# Generated by FakeRAM 2.0
VERSION 5.7 ;
BUSBITCHARS "[]" ;
PROPERTYDEFINITIONS
  MACRO width INTEGER ;
  MACRO depth INTEGER ;
  MACRO banks INTEGER ;
END PROPERTYDEFINITIONS
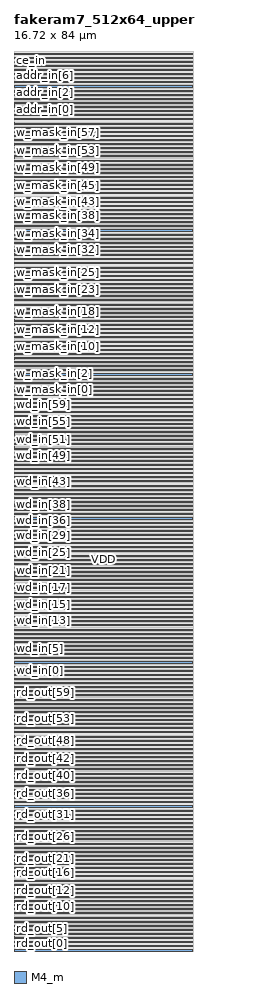
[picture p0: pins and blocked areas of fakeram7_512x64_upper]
MACRO fakeram7_512x64_upper
  PROPERTY width 64 ;
  PROPERTY depth 512 ;
  PROPERTY banks 2 ;
  FOREIGN fakeram7_512x64_upper 0 0 ;
  SYMMETRY X Y R90 ;
  SIZE 16.720 BY 84.000 ;
  CLASS COVER ;
  PIN rd_out[0]
    DIRECTION OUTPUT ;
    USE SIGNAL ;
    SHAPE ABUTMENT ;
    PORT
      LAYER M4_m ;
      RECT 0.000 0.039 0.024 0.063 ;
    END
  END rd_out[0]
  PIN rd_out[1]
    DIRECTION OUTPUT ;
    USE SIGNAL ;
    SHAPE ABUTMENT ;
    PORT
      LAYER M4_m ;
      RECT 0.000 0.471 0.024 0.495 ;
    END
  END rd_out[1]
  PIN rd_out[2]
    DIRECTION OUTPUT ;
    USE SIGNAL ;
    SHAPE ABUTMENT ;
    PORT
      LAYER M4_m ;
      RECT 0.000 0.855 0.024 0.879 ;
    END
  END rd_out[2]
  PIN rd_out[3]
    DIRECTION OUTPUT ;
    USE SIGNAL ;
    SHAPE ABUTMENT ;
    PORT
      LAYER M4_m ;
      RECT 0.000 1.287 0.024 1.311 ;
    END
  END rd_out[3]
  PIN rd_out[4]
    DIRECTION OUTPUT ;
    USE SIGNAL ;
    SHAPE ABUTMENT ;
    PORT
      LAYER M4_m ;
      RECT 0.000 1.671 0.024 1.695 ;
    END
  END rd_out[4]
  PIN rd_out[5]
    DIRECTION OUTPUT ;
    USE SIGNAL ;
    SHAPE ABUTMENT ;
    PORT
      LAYER M4_m ;
      RECT 0.000 2.103 0.024 2.127 ;
    END
  END rd_out[5]
  PIN rd_out[6]
    DIRECTION OUTPUT ;
    USE SIGNAL ;
    SHAPE ABUTMENT ;
    PORT
      LAYER M4_m ;
      RECT 0.000 2.487 0.024 2.511 ;
    END
  END rd_out[6]
  PIN rd_out[7]
    DIRECTION OUTPUT ;
    USE SIGNAL ;
    SHAPE ABUTMENT ;
    PORT
      LAYER M4_m ;
      RECT 0.000 2.919 0.024 2.943 ;
    END
  END rd_out[7]
  PIN rd_out[8]
    DIRECTION OUTPUT ;
    USE SIGNAL ;
    SHAPE ABUTMENT ;
    PORT
      LAYER M4_m ;
      RECT 0.000 3.303 0.024 3.327 ;
    END
  END rd_out[8]
  PIN rd_out[9]
    DIRECTION OUTPUT ;
    USE SIGNAL ;
    SHAPE ABUTMENT ;
    PORT
      LAYER M4_m ;
      RECT 0.000 3.735 0.024 3.759 ;
    END
  END rd_out[9]
  PIN rd_out[10]
    DIRECTION OUTPUT ;
    USE SIGNAL ;
    SHAPE ABUTMENT ;
    PORT
      LAYER M4_m ;
      RECT 0.000 4.119 0.024 4.143 ;
    END
  END rd_out[10]
  PIN rd_out[11]
    DIRECTION OUTPUT ;
    USE SIGNAL ;
    SHAPE ABUTMENT ;
    PORT
      LAYER M4_m ;
      RECT 0.000 4.551 0.024 4.575 ;
    END
  END rd_out[11]
  PIN rd_out[12]
    DIRECTION OUTPUT ;
    USE SIGNAL ;
    SHAPE ABUTMENT ;
    PORT
      LAYER M4_m ;
      RECT 0.000 4.935 0.024 4.959 ;
    END
  END rd_out[12]
  PIN rd_out[13]
    DIRECTION OUTPUT ;
    USE SIGNAL ;
    SHAPE ABUTMENT ;
    PORT
      LAYER M4_m ;
      RECT 0.000 5.367 0.024 5.391 ;
    END
  END rd_out[13]
  PIN rd_out[14]
    DIRECTION OUTPUT ;
    USE SIGNAL ;
    SHAPE ABUTMENT ;
    PORT
      LAYER M4_m ;
      RECT 0.000 5.751 0.024 5.775 ;
    END
  END rd_out[14]
  PIN rd_out[15]
    DIRECTION OUTPUT ;
    USE SIGNAL ;
    SHAPE ABUTMENT ;
    PORT
      LAYER M4_m ;
      RECT 0.000 6.183 0.024 6.207 ;
    END
  END rd_out[15]
  PIN rd_out[16]
    DIRECTION OUTPUT ;
    USE SIGNAL ;
    SHAPE ABUTMENT ;
    PORT
      LAYER M4_m ;
      RECT 0.000 6.567 0.024 6.591 ;
    END
  END rd_out[16]
  PIN rd_out[17]
    DIRECTION OUTPUT ;
    USE SIGNAL ;
    SHAPE ABUTMENT ;
    PORT
      LAYER M4_m ;
      RECT 0.000 6.999 0.024 7.023 ;
    END
  END rd_out[17]
  PIN rd_out[18]
    DIRECTION OUTPUT ;
    USE SIGNAL ;
    SHAPE ABUTMENT ;
    PORT
      LAYER M4_m ;
      RECT 0.000 7.383 0.024 7.407 ;
    END
  END rd_out[18]
  PIN rd_out[19]
    DIRECTION OUTPUT ;
    USE SIGNAL ;
    SHAPE ABUTMENT ;
    PORT
      LAYER M4_m ;
      RECT 0.000 7.815 0.024 7.839 ;
    END
  END rd_out[19]
  PIN rd_out[20]
    DIRECTION OUTPUT ;
    USE SIGNAL ;
    SHAPE ABUTMENT ;
    PORT
      LAYER M4_m ;
      RECT 0.000 8.199 0.024 8.223 ;
    END
  END rd_out[20]
  PIN rd_out[21]
    DIRECTION OUTPUT ;
    USE SIGNAL ;
    SHAPE ABUTMENT ;
    PORT
      LAYER M4_m ;
      RECT 0.000 8.631 0.024 8.655 ;
    END
  END rd_out[21]
  PIN rd_out[22]
    DIRECTION OUTPUT ;
    USE SIGNAL ;
    SHAPE ABUTMENT ;
    PORT
      LAYER M4_m ;
      RECT 0.000 9.015 0.024 9.039 ;
    END
  END rd_out[22]
  PIN rd_out[23]
    DIRECTION OUTPUT ;
    USE SIGNAL ;
    SHAPE ABUTMENT ;
    PORT
      LAYER M4_m ;
      RECT 0.000 9.447 0.024 9.471 ;
    END
  END rd_out[23]
  PIN rd_out[24]
    DIRECTION OUTPUT ;
    USE SIGNAL ;
    SHAPE ABUTMENT ;
    PORT
      LAYER M4_m ;
      RECT 0.000 9.831 0.024 9.855 ;
    END
  END rd_out[24]
  PIN rd_out[25]
    DIRECTION OUTPUT ;
    USE SIGNAL ;
    SHAPE ABUTMENT ;
    PORT
      LAYER M4_m ;
      RECT 0.000 10.263 0.024 10.287 ;
    END
  END rd_out[25]
  PIN rd_out[26]
    DIRECTION OUTPUT ;
    USE SIGNAL ;
    SHAPE ABUTMENT ;
    PORT
      LAYER M4_m ;
      RECT 0.000 10.647 0.024 10.671 ;
    END
  END rd_out[26]
  PIN rd_out[27]
    DIRECTION OUTPUT ;
    USE SIGNAL ;
    SHAPE ABUTMENT ;
    PORT
      LAYER M4_m ;
      RECT 0.000 11.079 0.024 11.103 ;
    END
  END rd_out[27]
  PIN rd_out[28]
    DIRECTION OUTPUT ;
    USE SIGNAL ;
    SHAPE ABUTMENT ;
    PORT
      LAYER M4_m ;
      RECT 0.000 11.463 0.024 11.487 ;
    END
  END rd_out[28]
  PIN rd_out[29]
    DIRECTION OUTPUT ;
    USE SIGNAL ;
    SHAPE ABUTMENT ;
    PORT
      LAYER M4_m ;
      RECT 0.000 11.895 0.024 11.919 ;
    END
  END rd_out[29]
  PIN rd_out[30]
    DIRECTION OUTPUT ;
    USE SIGNAL ;
    SHAPE ABUTMENT ;
    PORT
      LAYER M4_m ;
      RECT 0.000 12.279 0.024 12.303 ;
    END
  END rd_out[30]
  PIN rd_out[31]
    DIRECTION OUTPUT ;
    USE SIGNAL ;
    SHAPE ABUTMENT ;
    PORT
      LAYER M4_m ;
      RECT 0.000 12.711 0.024 12.735 ;
    END
  END rd_out[31]
  PIN rd_out[32]
    DIRECTION OUTPUT ;
    USE SIGNAL ;
    SHAPE ABUTMENT ;
    PORT
      LAYER M4_m ;
      RECT 0.000 13.095 0.024 13.119 ;
    END
  END rd_out[32]
  PIN rd_out[33]
    DIRECTION OUTPUT ;
    USE SIGNAL ;
    SHAPE ABUTMENT ;
    PORT
      LAYER M4_m ;
      RECT 0.000 13.527 0.024 13.551 ;
    END
  END rd_out[33]
  PIN rd_out[34]
    DIRECTION OUTPUT ;
    USE SIGNAL ;
    SHAPE ABUTMENT ;
    PORT
      LAYER M4_m ;
      RECT 0.000 13.911 0.024 13.935 ;
    END
  END rd_out[34]
  PIN rd_out[35]
    DIRECTION OUTPUT ;
    USE SIGNAL ;
    SHAPE ABUTMENT ;
    PORT
      LAYER M4_m ;
      RECT 0.000 14.343 0.024 14.367 ;
    END
  END rd_out[35]
  PIN rd_out[36]
    DIRECTION OUTPUT ;
    USE SIGNAL ;
    SHAPE ABUTMENT ;
    PORT
      LAYER M4_m ;
      RECT 0.000 14.727 0.024 14.751 ;
    END
  END rd_out[36]
  PIN rd_out[37]
    DIRECTION OUTPUT ;
    USE SIGNAL ;
    SHAPE ABUTMENT ;
    PORT
      LAYER M4_m ;
      RECT 0.000 15.159 0.024 15.183 ;
    END
  END rd_out[37]
  PIN rd_out[38]
    DIRECTION OUTPUT ;
    USE SIGNAL ;
    SHAPE ABUTMENT ;
    PORT
      LAYER M4_m ;
      RECT 0.000 15.543 0.024 15.567 ;
    END
  END rd_out[38]
  PIN rd_out[39]
    DIRECTION OUTPUT ;
    USE SIGNAL ;
    SHAPE ABUTMENT ;
    PORT
      LAYER M4_m ;
      RECT 0.000 15.975 0.024 15.999 ;
    END
  END rd_out[39]
  PIN rd_out[40]
    DIRECTION OUTPUT ;
    USE SIGNAL ;
    SHAPE ABUTMENT ;
    PORT
      LAYER M4_m ;
      RECT 0.000 16.359 0.024 16.383 ;
    END
  END rd_out[40]
  PIN rd_out[41]
    DIRECTION OUTPUT ;
    USE SIGNAL ;
    SHAPE ABUTMENT ;
    PORT
      LAYER M4_m ;
      RECT 0.000 16.791 0.024 16.815 ;
    END
  END rd_out[41]
  PIN rd_out[42]
    DIRECTION OUTPUT ;
    USE SIGNAL ;
    SHAPE ABUTMENT ;
    PORT
      LAYER M4_m ;
      RECT 0.000 17.175 0.024 17.199 ;
    END
  END rd_out[42]
  PIN rd_out[43]
    DIRECTION OUTPUT ;
    USE SIGNAL ;
    SHAPE ABUTMENT ;
    PORT
      LAYER M4_m ;
      RECT 0.000 17.607 0.024 17.631 ;
    END
  END rd_out[43]
  PIN rd_out[44]
    DIRECTION OUTPUT ;
    USE SIGNAL ;
    SHAPE ABUTMENT ;
    PORT
      LAYER M4_m ;
      RECT 0.000 17.991 0.024 18.015 ;
    END
  END rd_out[44]
  PIN rd_out[45]
    DIRECTION OUTPUT ;
    USE SIGNAL ;
    SHAPE ABUTMENT ;
    PORT
      LAYER M4_m ;
      RECT 0.000 18.423 0.024 18.447 ;
    END
  END rd_out[45]
  PIN rd_out[46]
    DIRECTION OUTPUT ;
    USE SIGNAL ;
    SHAPE ABUTMENT ;
    PORT
      LAYER M4_m ;
      RECT 0.000 18.807 0.024 18.831 ;
    END
  END rd_out[46]
  PIN rd_out[47]
    DIRECTION OUTPUT ;
    USE SIGNAL ;
    SHAPE ABUTMENT ;
    PORT
      LAYER M4_m ;
      RECT 0.000 19.239 0.024 19.263 ;
    END
  END rd_out[47]
  PIN rd_out[48]
    DIRECTION OUTPUT ;
    USE SIGNAL ;
    SHAPE ABUTMENT ;
    PORT
      LAYER M4_m ;
      RECT 0.000 19.623 0.024 19.647 ;
    END
  END rd_out[48]
  PIN rd_out[49]
    DIRECTION OUTPUT ;
    USE SIGNAL ;
    SHAPE ABUTMENT ;
    PORT
      LAYER M4_m ;
      RECT 0.000 20.055 0.024 20.079 ;
    END
  END rd_out[49]
  PIN rd_out[50]
    DIRECTION OUTPUT ;
    USE SIGNAL ;
    SHAPE ABUTMENT ;
    PORT
      LAYER M4_m ;
      RECT 0.000 20.439 0.024 20.463 ;
    END
  END rd_out[50]
  PIN rd_out[51]
    DIRECTION OUTPUT ;
    USE SIGNAL ;
    SHAPE ABUTMENT ;
    PORT
      LAYER M4_m ;
      RECT 0.000 20.871 0.024 20.895 ;
    END
  END rd_out[51]
  PIN rd_out[52]
    DIRECTION OUTPUT ;
    USE SIGNAL ;
    SHAPE ABUTMENT ;
    PORT
      LAYER M4_m ;
      RECT 0.000 21.255 0.024 21.279 ;
    END
  END rd_out[52]
  PIN rd_out[53]
    DIRECTION OUTPUT ;
    USE SIGNAL ;
    SHAPE ABUTMENT ;
    PORT
      LAYER M4_m ;
      RECT 0.000 21.687 0.024 21.711 ;
    END
  END rd_out[53]
  PIN rd_out[54]
    DIRECTION OUTPUT ;
    USE SIGNAL ;
    SHAPE ABUTMENT ;
    PORT
      LAYER M4_m ;
      RECT 0.000 22.071 0.024 22.095 ;
    END
  END rd_out[54]
  PIN rd_out[55]
    DIRECTION OUTPUT ;
    USE SIGNAL ;
    SHAPE ABUTMENT ;
    PORT
      LAYER M4_m ;
      RECT 0.000 22.503 0.024 22.527 ;
    END
  END rd_out[55]
  PIN rd_out[56]
    DIRECTION OUTPUT ;
    USE SIGNAL ;
    SHAPE ABUTMENT ;
    PORT
      LAYER M4_m ;
      RECT 0.000 22.887 0.024 22.911 ;
    END
  END rd_out[56]
  PIN rd_out[57]
    DIRECTION OUTPUT ;
    USE SIGNAL ;
    SHAPE ABUTMENT ;
    PORT
      LAYER M4_m ;
      RECT 0.000 23.319 0.024 23.343 ;
    END
  END rd_out[57]
  PIN rd_out[58]
    DIRECTION OUTPUT ;
    USE SIGNAL ;
    SHAPE ABUTMENT ;
    PORT
      LAYER M4_m ;
      RECT 0.000 23.703 0.024 23.727 ;
    END
  END rd_out[58]
  PIN rd_out[59]
    DIRECTION OUTPUT ;
    USE SIGNAL ;
    SHAPE ABUTMENT ;
    PORT
      LAYER M4_m ;
      RECT 0.000 24.135 0.024 24.159 ;
    END
  END rd_out[59]
  PIN rd_out[60]
    DIRECTION OUTPUT ;
    USE SIGNAL ;
    SHAPE ABUTMENT ;
    PORT
      LAYER M4_m ;
      RECT 0.000 24.519 0.024 24.543 ;
    END
  END rd_out[60]
  PIN rd_out[61]
    DIRECTION OUTPUT ;
    USE SIGNAL ;
    SHAPE ABUTMENT ;
    PORT
      LAYER M4_m ;
      RECT 0.000 24.951 0.024 24.975 ;
    END
  END rd_out[61]
  PIN rd_out[62]
    DIRECTION OUTPUT ;
    USE SIGNAL ;
    SHAPE ABUTMENT ;
    PORT
      LAYER M4_m ;
      RECT 0.000 25.335 0.024 25.359 ;
    END
  END rd_out[62]
  PIN rd_out[63]
    DIRECTION OUTPUT ;
    USE SIGNAL ;
    SHAPE ABUTMENT ;
    PORT
      LAYER M4_m ;
      RECT 0.000 25.767 0.024 25.791 ;
    END
  END rd_out[63]
  PIN wd_in[0]
    DIRECTION INPUT ;
    USE SIGNAL ;
    SHAPE ABUTMENT ;
    PORT
      LAYER M4_m ;
      RECT 0.000 26.199 0.024 26.223 ;
    END
  END wd_in[0]
  PIN wd_in[1]
    DIRECTION INPUT ;
    USE SIGNAL ;
    SHAPE ABUTMENT ;
    PORT
      LAYER M4_m ;
      RECT 0.000 26.631 0.024 26.655 ;
    END
  END wd_in[1]
  PIN wd_in[2]
    DIRECTION INPUT ;
    USE SIGNAL ;
    SHAPE ABUTMENT ;
    PORT
      LAYER M4_m ;
      RECT 0.000 27.015 0.024 27.039 ;
    END
  END wd_in[2]
  PIN wd_in[3]
    DIRECTION INPUT ;
    USE SIGNAL ;
    SHAPE ABUTMENT ;
    PORT
      LAYER M4_m ;
      RECT 0.000 27.447 0.024 27.471 ;
    END
  END wd_in[3]
  PIN wd_in[4]
    DIRECTION INPUT ;
    USE SIGNAL ;
    SHAPE ABUTMENT ;
    PORT
      LAYER M4_m ;
      RECT 0.000 27.831 0.024 27.855 ;
    END
  END wd_in[4]
  PIN wd_in[5]
    DIRECTION INPUT ;
    USE SIGNAL ;
    SHAPE ABUTMENT ;
    PORT
      LAYER M4_m ;
      RECT 0.000 28.263 0.024 28.287 ;
    END
  END wd_in[5]
  PIN wd_in[6]
    DIRECTION INPUT ;
    USE SIGNAL ;
    SHAPE ABUTMENT ;
    PORT
      LAYER M4_m ;
      RECT 0.000 28.647 0.024 28.671 ;
    END
  END wd_in[6]
  PIN wd_in[7]
    DIRECTION INPUT ;
    USE SIGNAL ;
    SHAPE ABUTMENT ;
    PORT
      LAYER M4_m ;
      RECT 0.000 29.079 0.024 29.103 ;
    END
  END wd_in[7]
  PIN wd_in[8]
    DIRECTION INPUT ;
    USE SIGNAL ;
    SHAPE ABUTMENT ;
    PORT
      LAYER M4_m ;
      RECT 0.000 29.463 0.024 29.487 ;
    END
  END wd_in[8]
  PIN wd_in[9]
    DIRECTION INPUT ;
    USE SIGNAL ;
    SHAPE ABUTMENT ;
    PORT
      LAYER M4_m ;
      RECT 0.000 29.895 0.024 29.919 ;
    END
  END wd_in[9]
  PIN wd_in[10]
    DIRECTION INPUT ;
    USE SIGNAL ;
    SHAPE ABUTMENT ;
    PORT
      LAYER M4_m ;
      RECT 0.000 30.279 0.024 30.303 ;
    END
  END wd_in[10]
  PIN wd_in[11]
    DIRECTION INPUT ;
    USE SIGNAL ;
    SHAPE ABUTMENT ;
    PORT
      LAYER M4_m ;
      RECT 0.000 30.711 0.024 30.735 ;
    END
  END wd_in[11]
  PIN wd_in[12]
    DIRECTION INPUT ;
    USE SIGNAL ;
    SHAPE ABUTMENT ;
    PORT
      LAYER M4_m ;
      RECT 0.000 31.095 0.024 31.119 ;
    END
  END wd_in[12]
  PIN wd_in[13]
    DIRECTION INPUT ;
    USE SIGNAL ;
    SHAPE ABUTMENT ;
    PORT
      LAYER M4_m ;
      RECT 0.000 31.527 0.024 31.551 ;
    END
  END wd_in[13]
  PIN wd_in[14]
    DIRECTION INPUT ;
    USE SIGNAL ;
    SHAPE ABUTMENT ;
    PORT
      LAYER M4_m ;
      RECT 0.000 31.911 0.024 31.935 ;
    END
  END wd_in[14]
  PIN wd_in[15]
    DIRECTION INPUT ;
    USE SIGNAL ;
    SHAPE ABUTMENT ;
    PORT
      LAYER M4_m ;
      RECT 0.000 32.343 0.024 32.367 ;
    END
  END wd_in[15]
  PIN wd_in[16]
    DIRECTION INPUT ;
    USE SIGNAL ;
    SHAPE ABUTMENT ;
    PORT
      LAYER M4_m ;
      RECT 0.000 32.727 0.024 32.751 ;
    END
  END wd_in[16]
  PIN wd_in[17]
    DIRECTION INPUT ;
    USE SIGNAL ;
    SHAPE ABUTMENT ;
    PORT
      LAYER M4_m ;
      RECT 0.000 33.159 0.024 33.183 ;
    END
  END wd_in[17]
  PIN wd_in[18]
    DIRECTION INPUT ;
    USE SIGNAL ;
    SHAPE ABUTMENT ;
    PORT
      LAYER M4_m ;
      RECT 0.000 33.543 0.024 33.567 ;
    END
  END wd_in[18]
  PIN wd_in[19]
    DIRECTION INPUT ;
    USE SIGNAL ;
    SHAPE ABUTMENT ;
    PORT
      LAYER M4_m ;
      RECT 0.000 33.975 0.024 33.999 ;
    END
  END wd_in[19]
  PIN wd_in[20]
    DIRECTION INPUT ;
    USE SIGNAL ;
    SHAPE ABUTMENT ;
    PORT
      LAYER M4_m ;
      RECT 0.000 34.359 0.024 34.383 ;
    END
  END wd_in[20]
  PIN wd_in[21]
    DIRECTION INPUT ;
    USE SIGNAL ;
    SHAPE ABUTMENT ;
    PORT
      LAYER M4_m ;
      RECT 0.000 34.791 0.024 34.815 ;
    END
  END wd_in[21]
  PIN wd_in[22]
    DIRECTION INPUT ;
    USE SIGNAL ;
    SHAPE ABUTMENT ;
    PORT
      LAYER M4_m ;
      RECT 0.000 35.175 0.024 35.199 ;
    END
  END wd_in[22]
  PIN wd_in[23]
    DIRECTION INPUT ;
    USE SIGNAL ;
    SHAPE ABUTMENT ;
    PORT
      LAYER M4_m ;
      RECT 0.000 35.607 0.024 35.631 ;
    END
  END wd_in[23]
  PIN wd_in[24]
    DIRECTION INPUT ;
    USE SIGNAL ;
    SHAPE ABUTMENT ;
    PORT
      LAYER M4_m ;
      RECT 0.000 35.991 0.024 36.015 ;
    END
  END wd_in[24]
  PIN wd_in[25]
    DIRECTION INPUT ;
    USE SIGNAL ;
    SHAPE ABUTMENT ;
    PORT
      LAYER M4_m ;
      RECT 0.000 36.423 0.024 36.447 ;
    END
  END wd_in[25]
  PIN wd_in[26]
    DIRECTION INPUT ;
    USE SIGNAL ;
    SHAPE ABUTMENT ;
    PORT
      LAYER M4_m ;
      RECT 0.000 36.807 0.024 36.831 ;
    END
  END wd_in[26]
  PIN wd_in[27]
    DIRECTION INPUT ;
    USE SIGNAL ;
    SHAPE ABUTMENT ;
    PORT
      LAYER M4_m ;
      RECT 0.000 37.239 0.024 37.263 ;
    END
  END wd_in[27]
  PIN wd_in[28]
    DIRECTION INPUT ;
    USE SIGNAL ;
    SHAPE ABUTMENT ;
    PORT
      LAYER M4_m ;
      RECT 0.000 37.623 0.024 37.647 ;
    END
  END wd_in[28]
  PIN wd_in[29]
    DIRECTION INPUT ;
    USE SIGNAL ;
    SHAPE ABUTMENT ;
    PORT
      LAYER M4_m ;
      RECT 0.000 38.055 0.024 38.079 ;
    END
  END wd_in[29]
  PIN wd_in[30]
    DIRECTION INPUT ;
    USE SIGNAL ;
    SHAPE ABUTMENT ;
    PORT
      LAYER M4_m ;
      RECT 0.000 38.439 0.024 38.463 ;
    END
  END wd_in[30]
  PIN wd_in[31]
    DIRECTION INPUT ;
    USE SIGNAL ;
    SHAPE ABUTMENT ;
    PORT
      LAYER M4_m ;
      RECT 0.000 38.871 0.024 38.895 ;
    END
  END wd_in[31]
  PIN wd_in[32]
    DIRECTION INPUT ;
    USE SIGNAL ;
    SHAPE ABUTMENT ;
    PORT
      LAYER M4_m ;
      RECT 0.000 39.255 0.024 39.279 ;
    END
  END wd_in[32]
  PIN wd_in[33]
    DIRECTION INPUT ;
    USE SIGNAL ;
    SHAPE ABUTMENT ;
    PORT
      LAYER M4_m ;
      RECT 0.000 39.687 0.024 39.711 ;
    END
  END wd_in[33]
  PIN wd_in[34]
    DIRECTION INPUT ;
    USE SIGNAL ;
    SHAPE ABUTMENT ;
    PORT
      LAYER M4_m ;
      RECT 0.000 40.071 0.024 40.095 ;
    END
  END wd_in[34]
  PIN wd_in[35]
    DIRECTION INPUT ;
    USE SIGNAL ;
    SHAPE ABUTMENT ;
    PORT
      LAYER M4_m ;
      RECT 0.000 40.503 0.024 40.527 ;
    END
  END wd_in[35]
  PIN wd_in[36]
    DIRECTION INPUT ;
    USE SIGNAL ;
    SHAPE ABUTMENT ;
    PORT
      LAYER M4_m ;
      RECT 0.000 40.887 0.024 40.911 ;
    END
  END wd_in[36]
  PIN wd_in[37]
    DIRECTION INPUT ;
    USE SIGNAL ;
    SHAPE ABUTMENT ;
    PORT
      LAYER M4_m ;
      RECT 0.000 41.319 0.024 41.343 ;
    END
  END wd_in[37]
  PIN wd_in[38]
    DIRECTION INPUT ;
    USE SIGNAL ;
    SHAPE ABUTMENT ;
    PORT
      LAYER M4_m ;
      RECT 0.000 41.703 0.024 41.727 ;
    END
  END wd_in[38]
  PIN wd_in[39]
    DIRECTION INPUT ;
    USE SIGNAL ;
    SHAPE ABUTMENT ;
    PORT
      LAYER M4_m ;
      RECT 0.000 42.135 0.024 42.159 ;
    END
  END wd_in[39]
  PIN wd_in[40]
    DIRECTION INPUT ;
    USE SIGNAL ;
    SHAPE ABUTMENT ;
    PORT
      LAYER M4_m ;
      RECT 0.000 42.519 0.024 42.543 ;
    END
  END wd_in[40]
  PIN wd_in[41]
    DIRECTION INPUT ;
    USE SIGNAL ;
    SHAPE ABUTMENT ;
    PORT
      LAYER M4_m ;
      RECT 0.000 42.951 0.024 42.975 ;
    END
  END wd_in[41]
  PIN wd_in[42]
    DIRECTION INPUT ;
    USE SIGNAL ;
    SHAPE ABUTMENT ;
    PORT
      LAYER M4_m ;
      RECT 0.000 43.335 0.024 43.359 ;
    END
  END wd_in[42]
  PIN wd_in[43]
    DIRECTION INPUT ;
    USE SIGNAL ;
    SHAPE ABUTMENT ;
    PORT
      LAYER M4_m ;
      RECT 0.000 43.767 0.024 43.791 ;
    END
  END wd_in[43]
  PIN wd_in[44]
    DIRECTION INPUT ;
    USE SIGNAL ;
    SHAPE ABUTMENT ;
    PORT
      LAYER M4_m ;
      RECT 0.000 44.151 0.024 44.175 ;
    END
  END wd_in[44]
  PIN wd_in[45]
    DIRECTION INPUT ;
    USE SIGNAL ;
    SHAPE ABUTMENT ;
    PORT
      LAYER M4_m ;
      RECT 0.000 44.583 0.024 44.607 ;
    END
  END wd_in[45]
  PIN wd_in[46]
    DIRECTION INPUT ;
    USE SIGNAL ;
    SHAPE ABUTMENT ;
    PORT
      LAYER M4_m ;
      RECT 0.000 44.967 0.024 44.991 ;
    END
  END wd_in[46]
  PIN wd_in[47]
    DIRECTION INPUT ;
    USE SIGNAL ;
    SHAPE ABUTMENT ;
    PORT
      LAYER M4_m ;
      RECT 0.000 45.399 0.024 45.423 ;
    END
  END wd_in[47]
  PIN wd_in[48]
    DIRECTION INPUT ;
    USE SIGNAL ;
    SHAPE ABUTMENT ;
    PORT
      LAYER M4_m ;
      RECT 0.000 45.783 0.024 45.807 ;
    END
  END wd_in[48]
  PIN wd_in[49]
    DIRECTION INPUT ;
    USE SIGNAL ;
    SHAPE ABUTMENT ;
    PORT
      LAYER M4_m ;
      RECT 0.000 46.215 0.024 46.239 ;
    END
  END wd_in[49]
  PIN wd_in[50]
    DIRECTION INPUT ;
    USE SIGNAL ;
    SHAPE ABUTMENT ;
    PORT
      LAYER M4_m ;
      RECT 0.000 46.599 0.024 46.623 ;
    END
  END wd_in[50]
  PIN wd_in[51]
    DIRECTION INPUT ;
    USE SIGNAL ;
    SHAPE ABUTMENT ;
    PORT
      LAYER M4_m ;
      RECT 0.000 47.031 0.024 47.055 ;
    END
  END wd_in[51]
  PIN wd_in[52]
    DIRECTION INPUT ;
    USE SIGNAL ;
    SHAPE ABUTMENT ;
    PORT
      LAYER M4_m ;
      RECT 0.000 47.415 0.024 47.439 ;
    END
  END wd_in[52]
  PIN wd_in[53]
    DIRECTION INPUT ;
    USE SIGNAL ;
    SHAPE ABUTMENT ;
    PORT
      LAYER M4_m ;
      RECT 0.000 47.847 0.024 47.871 ;
    END
  END wd_in[53]
  PIN wd_in[54]
    DIRECTION INPUT ;
    USE SIGNAL ;
    SHAPE ABUTMENT ;
    PORT
      LAYER M4_m ;
      RECT 0.000 48.231 0.024 48.255 ;
    END
  END wd_in[54]
  PIN wd_in[55]
    DIRECTION INPUT ;
    USE SIGNAL ;
    SHAPE ABUTMENT ;
    PORT
      LAYER M4_m ;
      RECT 0.000 48.663 0.024 48.687 ;
    END
  END wd_in[55]
  PIN wd_in[56]
    DIRECTION INPUT ;
    USE SIGNAL ;
    SHAPE ABUTMENT ;
    PORT
      LAYER M4_m ;
      RECT 0.000 49.047 0.024 49.071 ;
    END
  END wd_in[56]
  PIN wd_in[57]
    DIRECTION INPUT ;
    USE SIGNAL ;
    SHAPE ABUTMENT ;
    PORT
      LAYER M4_m ;
      RECT 0.000 49.479 0.024 49.503 ;
    END
  END wd_in[57]
  PIN wd_in[58]
    DIRECTION INPUT ;
    USE SIGNAL ;
    SHAPE ABUTMENT ;
    PORT
      LAYER M4_m ;
      RECT 0.000 49.863 0.024 49.887 ;
    END
  END wd_in[58]
  PIN wd_in[59]
    DIRECTION INPUT ;
    USE SIGNAL ;
    SHAPE ABUTMENT ;
    PORT
      LAYER M4_m ;
      RECT 0.000 50.295 0.024 50.319 ;
    END
  END wd_in[59]
  PIN wd_in[60]
    DIRECTION INPUT ;
    USE SIGNAL ;
    SHAPE ABUTMENT ;
    PORT
      LAYER M4_m ;
      RECT 0.000 50.679 0.024 50.703 ;
    END
  END wd_in[60]
  PIN wd_in[61]
    DIRECTION INPUT ;
    USE SIGNAL ;
    SHAPE ABUTMENT ;
    PORT
      LAYER M4_m ;
      RECT 0.000 51.111 0.024 51.135 ;
    END
  END wd_in[61]
  PIN wd_in[62]
    DIRECTION INPUT ;
    USE SIGNAL ;
    SHAPE ABUTMENT ;
    PORT
      LAYER M4_m ;
      RECT 0.000 51.495 0.024 51.519 ;
    END
  END wd_in[62]
  PIN wd_in[63]
    DIRECTION INPUT ;
    USE SIGNAL ;
    SHAPE ABUTMENT ;
    PORT
      LAYER M4_m ;
      RECT 0.000 51.927 0.024 51.951 ;
    END
  END wd_in[63]
  PIN w_mask_in[0]
    DIRECTION INPUT ;
    USE SIGNAL ;
    SHAPE ABUTMENT ;
    PORT
      LAYER M4_m ;
      RECT 0.000 52.359 0.024 52.383 ;
    END
  END w_mask_in[0]
  PIN w_mask_in[1]
    DIRECTION INPUT ;
    USE SIGNAL ;
    SHAPE ABUTMENT ;
    PORT
      LAYER M4_m ;
      RECT 0.000 52.791 0.024 52.815 ;
    END
  END w_mask_in[1]
  PIN w_mask_in[2]
    DIRECTION INPUT ;
    USE SIGNAL ;
    SHAPE ABUTMENT ;
    PORT
      LAYER M4_m ;
      RECT 0.000 53.175 0.024 53.199 ;
    END
  END w_mask_in[2]
  PIN w_mask_in[3]
    DIRECTION INPUT ;
    USE SIGNAL ;
    SHAPE ABUTMENT ;
    PORT
      LAYER M4_m ;
      RECT 0.000 53.607 0.024 53.631 ;
    END
  END w_mask_in[3]
  PIN w_mask_in[4]
    DIRECTION INPUT ;
    USE SIGNAL ;
    SHAPE ABUTMENT ;
    PORT
      LAYER M4_m ;
      RECT 0.000 53.991 0.024 54.015 ;
    END
  END w_mask_in[4]
  PIN w_mask_in[5]
    DIRECTION INPUT ;
    USE SIGNAL ;
    SHAPE ABUTMENT ;
    PORT
      LAYER M4_m ;
      RECT 0.000 54.423 0.024 54.447 ;
    END
  END w_mask_in[5]
  PIN w_mask_in[6]
    DIRECTION INPUT ;
    USE SIGNAL ;
    SHAPE ABUTMENT ;
    PORT
      LAYER M4_m ;
      RECT 0.000 54.807 0.024 54.831 ;
    END
  END w_mask_in[6]
  PIN w_mask_in[7]
    DIRECTION INPUT ;
    USE SIGNAL ;
    SHAPE ABUTMENT ;
    PORT
      LAYER M4_m ;
      RECT 0.000 55.239 0.024 55.263 ;
    END
  END w_mask_in[7]
  PIN w_mask_in[8]
    DIRECTION INPUT ;
    USE SIGNAL ;
    SHAPE ABUTMENT ;
    PORT
      LAYER M4_m ;
      RECT 0.000 55.623 0.024 55.647 ;
    END
  END w_mask_in[8]
  PIN w_mask_in[9]
    DIRECTION INPUT ;
    USE SIGNAL ;
    SHAPE ABUTMENT ;
    PORT
      LAYER M4_m ;
      RECT 0.000 56.055 0.024 56.079 ;
    END
  END w_mask_in[9]
  PIN w_mask_in[10]
    DIRECTION INPUT ;
    USE SIGNAL ;
    SHAPE ABUTMENT ;
    PORT
      LAYER M4_m ;
      RECT 0.000 56.439 0.024 56.463 ;
    END
  END w_mask_in[10]
  PIN w_mask_in[11]
    DIRECTION INPUT ;
    USE SIGNAL ;
    SHAPE ABUTMENT ;
    PORT
      LAYER M4_m ;
      RECT 0.000 56.871 0.024 56.895 ;
    END
  END w_mask_in[11]
  PIN w_mask_in[12]
    DIRECTION INPUT ;
    USE SIGNAL ;
    SHAPE ABUTMENT ;
    PORT
      LAYER M4_m ;
      RECT 0.000 57.255 0.024 57.279 ;
    END
  END w_mask_in[12]
  PIN w_mask_in[13]
    DIRECTION INPUT ;
    USE SIGNAL ;
    SHAPE ABUTMENT ;
    PORT
      LAYER M4_m ;
      RECT 0.000 57.687 0.024 57.711 ;
    END
  END w_mask_in[13]
  PIN w_mask_in[14]
    DIRECTION INPUT ;
    USE SIGNAL ;
    SHAPE ABUTMENT ;
    PORT
      LAYER M4_m ;
      RECT 0.000 58.071 0.024 58.095 ;
    END
  END w_mask_in[14]
  PIN w_mask_in[15]
    DIRECTION INPUT ;
    USE SIGNAL ;
    SHAPE ABUTMENT ;
    PORT
      LAYER M4_m ;
      RECT 0.000 58.503 0.024 58.527 ;
    END
  END w_mask_in[15]
  PIN w_mask_in[16]
    DIRECTION INPUT ;
    USE SIGNAL ;
    SHAPE ABUTMENT ;
    PORT
      LAYER M4_m ;
      RECT 0.000 58.887 0.024 58.911 ;
    END
  END w_mask_in[16]
  PIN w_mask_in[17]
    DIRECTION INPUT ;
    USE SIGNAL ;
    SHAPE ABUTMENT ;
    PORT
      LAYER M4_m ;
      RECT 0.000 59.319 0.024 59.343 ;
    END
  END w_mask_in[17]
  PIN w_mask_in[18]
    DIRECTION INPUT ;
    USE SIGNAL ;
    SHAPE ABUTMENT ;
    PORT
      LAYER M4_m ;
      RECT 0.000 59.703 0.024 59.727 ;
    END
  END w_mask_in[18]
  PIN w_mask_in[19]
    DIRECTION INPUT ;
    USE SIGNAL ;
    SHAPE ABUTMENT ;
    PORT
      LAYER M4_m ;
      RECT 0.000 60.135 0.024 60.159 ;
    END
  END w_mask_in[19]
  PIN w_mask_in[20]
    DIRECTION INPUT ;
    USE SIGNAL ;
    SHAPE ABUTMENT ;
    PORT
      LAYER M4_m ;
      RECT 0.000 60.519 0.024 60.543 ;
    END
  END w_mask_in[20]
  PIN w_mask_in[21]
    DIRECTION INPUT ;
    USE SIGNAL ;
    SHAPE ABUTMENT ;
    PORT
      LAYER M4_m ;
      RECT 0.000 60.951 0.024 60.975 ;
    END
  END w_mask_in[21]
  PIN w_mask_in[22]
    DIRECTION INPUT ;
    USE SIGNAL ;
    SHAPE ABUTMENT ;
    PORT
      LAYER M4_m ;
      RECT 0.000 61.335 0.024 61.359 ;
    END
  END w_mask_in[22]
  PIN w_mask_in[23]
    DIRECTION INPUT ;
    USE SIGNAL ;
    SHAPE ABUTMENT ;
    PORT
      LAYER M4_m ;
      RECT 0.000 61.767 0.024 61.791 ;
    END
  END w_mask_in[23]
  PIN w_mask_in[24]
    DIRECTION INPUT ;
    USE SIGNAL ;
    SHAPE ABUTMENT ;
    PORT
      LAYER M4_m ;
      RECT 0.000 62.151 0.024 62.175 ;
    END
  END w_mask_in[24]
  PIN w_mask_in[25]
    DIRECTION INPUT ;
    USE SIGNAL ;
    SHAPE ABUTMENT ;
    PORT
      LAYER M4_m ;
      RECT 0.000 62.583 0.024 62.607 ;
    END
  END w_mask_in[25]
  PIN w_mask_in[26]
    DIRECTION INPUT ;
    USE SIGNAL ;
    SHAPE ABUTMENT ;
    PORT
      LAYER M4_m ;
      RECT 0.000 62.967 0.024 62.991 ;
    END
  END w_mask_in[26]
  PIN w_mask_in[27]
    DIRECTION INPUT ;
    USE SIGNAL ;
    SHAPE ABUTMENT ;
    PORT
      LAYER M4_m ;
      RECT 0.000 63.399 0.024 63.423 ;
    END
  END w_mask_in[27]
  PIN w_mask_in[28]
    DIRECTION INPUT ;
    USE SIGNAL ;
    SHAPE ABUTMENT ;
    PORT
      LAYER M4_m ;
      RECT 0.000 63.783 0.024 63.807 ;
    END
  END w_mask_in[28]
  PIN w_mask_in[29]
    DIRECTION INPUT ;
    USE SIGNAL ;
    SHAPE ABUTMENT ;
    PORT
      LAYER M4_m ;
      RECT 0.000 64.215 0.024 64.239 ;
    END
  END w_mask_in[29]
  PIN w_mask_in[30]
    DIRECTION INPUT ;
    USE SIGNAL ;
    SHAPE ABUTMENT ;
    PORT
      LAYER M4_m ;
      RECT 0.000 64.599 0.024 64.623 ;
    END
  END w_mask_in[30]
  PIN w_mask_in[31]
    DIRECTION INPUT ;
    USE SIGNAL ;
    SHAPE ABUTMENT ;
    PORT
      LAYER M4_m ;
      RECT 0.000 65.031 0.024 65.055 ;
    END
  END w_mask_in[31]
  PIN w_mask_in[32]
    DIRECTION INPUT ;
    USE SIGNAL ;
    SHAPE ABUTMENT ;
    PORT
      LAYER M4_m ;
      RECT 0.000 65.415 0.024 65.439 ;
    END
  END w_mask_in[32]
  PIN w_mask_in[33]
    DIRECTION INPUT ;
    USE SIGNAL ;
    SHAPE ABUTMENT ;
    PORT
      LAYER M4_m ;
      RECT 0.000 65.847 0.024 65.871 ;
    END
  END w_mask_in[33]
  PIN w_mask_in[34]
    DIRECTION INPUT ;
    USE SIGNAL ;
    SHAPE ABUTMENT ;
    PORT
      LAYER M4_m ;
      RECT 0.000 66.231 0.024 66.255 ;
    END
  END w_mask_in[34]
  PIN w_mask_in[35]
    DIRECTION INPUT ;
    USE SIGNAL ;
    SHAPE ABUTMENT ;
    PORT
      LAYER M4_m ;
      RECT 0.000 66.663 0.024 66.687 ;
    END
  END w_mask_in[35]
  PIN w_mask_in[36]
    DIRECTION INPUT ;
    USE SIGNAL ;
    SHAPE ABUTMENT ;
    PORT
      LAYER M4_m ;
      RECT 0.000 67.047 0.024 67.071 ;
    END
  END w_mask_in[36]
  PIN w_mask_in[37]
    DIRECTION INPUT ;
    USE SIGNAL ;
    SHAPE ABUTMENT ;
    PORT
      LAYER M4_m ;
      RECT 0.000 67.479 0.024 67.503 ;
    END
  END w_mask_in[37]
  PIN w_mask_in[38]
    DIRECTION INPUT ;
    USE SIGNAL ;
    SHAPE ABUTMENT ;
    PORT
      LAYER M4_m ;
      RECT 0.000 67.863 0.024 67.887 ;
    END
  END w_mask_in[38]
  PIN w_mask_in[39]
    DIRECTION INPUT ;
    USE SIGNAL ;
    SHAPE ABUTMENT ;
    PORT
      LAYER M4_m ;
      RECT 0.000 68.295 0.024 68.319 ;
    END
  END w_mask_in[39]
  PIN w_mask_in[40]
    DIRECTION INPUT ;
    USE SIGNAL ;
    SHAPE ABUTMENT ;
    PORT
      LAYER M4_m ;
      RECT 0.000 68.679 0.024 68.703 ;
    END
  END w_mask_in[40]
  PIN w_mask_in[41]
    DIRECTION INPUT ;
    USE SIGNAL ;
    SHAPE ABUTMENT ;
    PORT
      LAYER M4_m ;
      RECT 0.000 69.111 0.024 69.135 ;
    END
  END w_mask_in[41]
  PIN w_mask_in[42]
    DIRECTION INPUT ;
    USE SIGNAL ;
    SHAPE ABUTMENT ;
    PORT
      LAYER M4_m ;
      RECT 0.000 69.495 0.024 69.519 ;
    END
  END w_mask_in[42]
  PIN w_mask_in[43]
    DIRECTION INPUT ;
    USE SIGNAL ;
    SHAPE ABUTMENT ;
    PORT
      LAYER M4_m ;
      RECT 0.000 69.927 0.024 69.951 ;
    END
  END w_mask_in[43]
  PIN w_mask_in[44]
    DIRECTION INPUT ;
    USE SIGNAL ;
    SHAPE ABUTMENT ;
    PORT
      LAYER M4_m ;
      RECT 0.000 70.311 0.024 70.335 ;
    END
  END w_mask_in[44]
  PIN w_mask_in[45]
    DIRECTION INPUT ;
    USE SIGNAL ;
    SHAPE ABUTMENT ;
    PORT
      LAYER M4_m ;
      RECT 0.000 70.743 0.024 70.767 ;
    END
  END w_mask_in[45]
  PIN w_mask_in[46]
    DIRECTION INPUT ;
    USE SIGNAL ;
    SHAPE ABUTMENT ;
    PORT
      LAYER M4_m ;
      RECT 0.000 71.127 0.024 71.151 ;
    END
  END w_mask_in[46]
  PIN w_mask_in[47]
    DIRECTION INPUT ;
    USE SIGNAL ;
    SHAPE ABUTMENT ;
    PORT
      LAYER M4_m ;
      RECT 0.000 71.559 0.024 71.583 ;
    END
  END w_mask_in[47]
  PIN w_mask_in[48]
    DIRECTION INPUT ;
    USE SIGNAL ;
    SHAPE ABUTMENT ;
    PORT
      LAYER M4_m ;
      RECT 0.000 71.943 0.024 71.967 ;
    END
  END w_mask_in[48]
  PIN w_mask_in[49]
    DIRECTION INPUT ;
    USE SIGNAL ;
    SHAPE ABUTMENT ;
    PORT
      LAYER M4_m ;
      RECT 0.000 72.375 0.024 72.399 ;
    END
  END w_mask_in[49]
  PIN w_mask_in[50]
    DIRECTION INPUT ;
    USE SIGNAL ;
    SHAPE ABUTMENT ;
    PORT
      LAYER M4_m ;
      RECT 0.000 72.759 0.024 72.783 ;
    END
  END w_mask_in[50]
  PIN w_mask_in[51]
    DIRECTION INPUT ;
    USE SIGNAL ;
    SHAPE ABUTMENT ;
    PORT
      LAYER M4_m ;
      RECT 0.000 73.191 0.024 73.215 ;
    END
  END w_mask_in[51]
  PIN w_mask_in[52]
    DIRECTION INPUT ;
    USE SIGNAL ;
    SHAPE ABUTMENT ;
    PORT
      LAYER M4_m ;
      RECT 0.000 73.575 0.024 73.599 ;
    END
  END w_mask_in[52]
  PIN w_mask_in[53]
    DIRECTION INPUT ;
    USE SIGNAL ;
    SHAPE ABUTMENT ;
    PORT
      LAYER M4_m ;
      RECT 0.000 74.007 0.024 74.031 ;
    END
  END w_mask_in[53]
  PIN w_mask_in[54]
    DIRECTION INPUT ;
    USE SIGNAL ;
    SHAPE ABUTMENT ;
    PORT
      LAYER M4_m ;
      RECT 0.000 74.391 0.024 74.415 ;
    END
  END w_mask_in[54]
  PIN w_mask_in[55]
    DIRECTION INPUT ;
    USE SIGNAL ;
    SHAPE ABUTMENT ;
    PORT
      LAYER M4_m ;
      RECT 0.000 74.823 0.024 74.847 ;
    END
  END w_mask_in[55]
  PIN w_mask_in[56]
    DIRECTION INPUT ;
    USE SIGNAL ;
    SHAPE ABUTMENT ;
    PORT
      LAYER M4_m ;
      RECT 0.000 75.207 0.024 75.231 ;
    END
  END w_mask_in[56]
  PIN w_mask_in[57]
    DIRECTION INPUT ;
    USE SIGNAL ;
    SHAPE ABUTMENT ;
    PORT
      LAYER M4_m ;
      RECT 0.000 75.639 0.024 75.663 ;
    END
  END w_mask_in[57]
  PIN w_mask_in[58]
    DIRECTION INPUT ;
    USE SIGNAL ;
    SHAPE ABUTMENT ;
    PORT
      LAYER M4_m ;
      RECT 0.000 76.023 0.024 76.047 ;
    END
  END w_mask_in[58]
  PIN w_mask_in[59]
    DIRECTION INPUT ;
    USE SIGNAL ;
    SHAPE ABUTMENT ;
    PORT
      LAYER M4_m ;
      RECT 0.000 76.455 0.024 76.479 ;
    END
  END w_mask_in[59]
  PIN w_mask_in[60]
    DIRECTION INPUT ;
    USE SIGNAL ;
    SHAPE ABUTMENT ;
    PORT
      LAYER M4_m ;
      RECT 0.000 76.839 0.024 76.863 ;
    END
  END w_mask_in[60]
  PIN w_mask_in[61]
    DIRECTION INPUT ;
    USE SIGNAL ;
    SHAPE ABUTMENT ;
    PORT
      LAYER M4_m ;
      RECT 0.000 77.271 0.024 77.295 ;
    END
  END w_mask_in[61]
  PIN w_mask_in[62]
    DIRECTION INPUT ;
    USE SIGNAL ;
    SHAPE ABUTMENT ;
    PORT
      LAYER M4_m ;
      RECT 0.000 77.655 0.024 77.679 ;
    END
  END w_mask_in[62]
  PIN w_mask_in[63]
    DIRECTION INPUT ;
    USE SIGNAL ;
    SHAPE ABUTMENT ;
    PORT
      LAYER M4_m ;
      RECT 0.000 78.087 0.024 78.111 ;
    END
  END w_mask_in[63]
  PIN addr_in[0]
    DIRECTION INPUT ;
    USE SIGNAL ;
    SHAPE ABUTMENT ;
    PORT
      LAYER M4_m ;
      RECT 0.000 78.519 0.024 78.543 ;
    END
  END addr_in[0]
  PIN addr_in[1]
    DIRECTION INPUT ;
    USE SIGNAL ;
    SHAPE ABUTMENT ;
    PORT
      LAYER M4_m ;
      RECT 0.000 78.951 0.024 78.975 ;
    END
  END addr_in[1]
  PIN addr_in[2]
    DIRECTION INPUT ;
    USE SIGNAL ;
    SHAPE ABUTMENT ;
    PORT
      LAYER M4_m ;
      RECT 0.000 79.335 0.024 79.359 ;
    END
  END addr_in[2]
  PIN addr_in[3]
    DIRECTION INPUT ;
    USE SIGNAL ;
    SHAPE ABUTMENT ;
    PORT
      LAYER M4_m ;
      RECT 0.000 79.767 0.024 79.791 ;
    END
  END addr_in[3]
  PIN addr_in[4]
    DIRECTION INPUT ;
    USE SIGNAL ;
    SHAPE ABUTMENT ;
    PORT
      LAYER M4_m ;
      RECT 0.000 80.151 0.024 80.175 ;
    END
  END addr_in[4]
  PIN addr_in[5]
    DIRECTION INPUT ;
    USE SIGNAL ;
    SHAPE ABUTMENT ;
    PORT
      LAYER M4_m ;
      RECT 0.000 80.583 0.024 80.607 ;
    END
  END addr_in[5]
  PIN addr_in[6]
    DIRECTION INPUT ;
    USE SIGNAL ;
    SHAPE ABUTMENT ;
    PORT
      LAYER M4_m ;
      RECT 0.000 80.967 0.024 80.991 ;
    END
  END addr_in[6]
  PIN addr_in[7]
    DIRECTION INPUT ;
    USE SIGNAL ;
    SHAPE ABUTMENT ;
    PORT
      LAYER M4_m ;
      RECT 0.000 81.399 0.024 81.423 ;
    END
  END addr_in[7]
  PIN addr_in[8]
    DIRECTION INPUT ;
    USE SIGNAL ;
    SHAPE ABUTMENT ;
    PORT
      LAYER M4_m ;
      RECT 0.000 81.783 0.024 81.807 ;
    END
  END addr_in[8]
  PIN we_in
    DIRECTION INPUT ;
    USE SIGNAL ;
    SHAPE ABUTMENT ;
    PORT
      LAYER M4_m ;
      RECT 0.000 82.263 0.024 82.287 ;
    END
  END we_in
  PIN ce_in
    DIRECTION INPUT ;
    USE SIGNAL ;
    SHAPE ABUTMENT ;
    PORT
      LAYER M4_m ;
      RECT 0.000 82.647 0.024 82.671 ;
    END
  END ce_in
  PIN clk
    DIRECTION INPUT ;
    USE SIGNAL ;
    SHAPE ABUTMENT ;
    PORT
      LAYER M4_m ;
      RECT 0.000 83.079 0.024 83.103 ;
    END
  END clk
  PIN VSS
    DIRECTION INOUT ;
    USE GROUND ;
    PORT
      LAYER M4_m ;
      RECT 0.048 0.000 16.672 0.096 ;
      RECT 0.048 0.768 16.672 0.864 ;
      RECT 0.048 1.536 16.672 1.632 ;
      RECT 0.048 2.304 16.672 2.400 ;
      RECT 0.048 3.072 16.672 3.168 ;
      RECT 0.048 3.840 16.672 3.936 ;
      RECT 0.048 4.608 16.672 4.704 ;
      RECT 0.048 5.376 16.672 5.472 ;
      RECT 0.048 6.144 16.672 6.240 ;
      RECT 0.048 6.912 16.672 7.008 ;
      RECT 0.048 7.680 16.672 7.776 ;
      RECT 0.048 8.448 16.672 8.544 ;
      RECT 0.048 9.216 16.672 9.312 ;
      RECT 0.048 9.984 16.672 10.080 ;
      RECT 0.048 10.752 16.672 10.848 ;
      RECT 0.048 11.520 16.672 11.616 ;
      RECT 0.048 12.288 16.672 12.384 ;
      RECT 0.048 13.056 16.672 13.152 ;
      RECT 0.048 13.824 16.672 13.920 ;
      RECT 0.048 14.592 16.672 14.688 ;
      RECT 0.048 15.360 16.672 15.456 ;
      RECT 0.048 16.128 16.672 16.224 ;
      RECT 0.048 16.896 16.672 16.992 ;
      RECT 0.048 17.664 16.672 17.760 ;
      RECT 0.048 18.432 16.672 18.528 ;
      RECT 0.048 19.200 16.672 19.296 ;
      RECT 0.048 19.968 16.672 20.064 ;
      RECT 0.048 20.736 16.672 20.832 ;
      RECT 0.048 21.504 16.672 21.600 ;
      RECT 0.048 22.272 16.672 22.368 ;
      RECT 0.048 23.040 16.672 23.136 ;
      RECT 0.048 23.808 16.672 23.904 ;
      RECT 0.048 24.576 16.672 24.672 ;
      RECT 0.048 25.344 16.672 25.440 ;
      RECT 0.048 26.112 16.672 26.208 ;
      RECT 0.048 26.880 16.672 26.976 ;
      RECT 0.048 27.648 16.672 27.744 ;
      RECT 0.048 28.416 16.672 28.512 ;
      RECT 0.048 29.184 16.672 29.280 ;
      RECT 0.048 29.952 16.672 30.048 ;
      RECT 0.048 30.720 16.672 30.816 ;
      RECT 0.048 31.488 16.672 31.584 ;
      RECT 0.048 32.256 16.672 32.352 ;
      RECT 0.048 33.024 16.672 33.120 ;
      RECT 0.048 33.792 16.672 33.888 ;
      RECT 0.048 34.560 16.672 34.656 ;
      RECT 0.048 35.328 16.672 35.424 ;
      RECT 0.048 36.096 16.672 36.192 ;
      RECT 0.048 36.864 16.672 36.960 ;
      RECT 0.048 37.632 16.672 37.728 ;
      RECT 0.048 38.400 16.672 38.496 ;
      RECT 0.048 39.168 16.672 39.264 ;
      RECT 0.048 39.936 16.672 40.032 ;
      RECT 0.048 40.704 16.672 40.800 ;
      RECT 0.048 41.472 16.672 41.568 ;
      RECT 0.048 42.240 16.672 42.336 ;
      RECT 0.048 43.008 16.672 43.104 ;
      RECT 0.048 43.776 16.672 43.872 ;
      RECT 0.048 44.544 16.672 44.640 ;
      RECT 0.048 45.312 16.672 45.408 ;
      RECT 0.048 46.080 16.672 46.176 ;
      RECT 0.048 46.848 16.672 46.944 ;
      RECT 0.048 47.616 16.672 47.712 ;
      RECT 0.048 48.384 16.672 48.480 ;
      RECT 0.048 49.152 16.672 49.248 ;
      RECT 0.048 49.920 16.672 50.016 ;
      RECT 0.048 50.688 16.672 50.784 ;
      RECT 0.048 51.456 16.672 51.552 ;
      RECT 0.048 52.224 16.672 52.320 ;
      RECT 0.048 52.992 16.672 53.088 ;
      RECT 0.048 53.760 16.672 53.856 ;
      RECT 0.048 54.528 16.672 54.624 ;
      RECT 0.048 55.296 16.672 55.392 ;
      RECT 0.048 56.064 16.672 56.160 ;
      RECT 0.048 56.832 16.672 56.928 ;
      RECT 0.048 57.600 16.672 57.696 ;
      RECT 0.048 58.368 16.672 58.464 ;
      RECT 0.048 59.136 16.672 59.232 ;
      RECT 0.048 59.904 16.672 60.000 ;
      RECT 0.048 60.672 16.672 60.768 ;
      RECT 0.048 61.440 16.672 61.536 ;
      RECT 0.048 62.208 16.672 62.304 ;
      RECT 0.048 62.976 16.672 63.072 ;
      RECT 0.048 63.744 16.672 63.840 ;
      RECT 0.048 64.512 16.672 64.608 ;
      RECT 0.048 65.280 16.672 65.376 ;
      RECT 0.048 66.048 16.672 66.144 ;
      RECT 0.048 66.816 16.672 66.912 ;
      RECT 0.048 67.584 16.672 67.680 ;
      RECT 0.048 68.352 16.672 68.448 ;
      RECT 0.048 69.120 16.672 69.216 ;
      RECT 0.048 69.888 16.672 69.984 ;
      RECT 0.048 70.656 16.672 70.752 ;
      RECT 0.048 71.424 16.672 71.520 ;
      RECT 0.048 72.192 16.672 72.288 ;
      RECT 0.048 72.960 16.672 73.056 ;
      RECT 0.048 73.728 16.672 73.824 ;
      RECT 0.048 74.496 16.672 74.592 ;
      RECT 0.048 75.264 16.672 75.360 ;
      RECT 0.048 76.032 16.672 76.128 ;
      RECT 0.048 76.800 16.672 76.896 ;
      RECT 0.048 77.568 16.672 77.664 ;
      RECT 0.048 78.336 16.672 78.432 ;
      RECT 0.048 79.104 16.672 79.200 ;
      RECT 0.048 79.872 16.672 79.968 ;
      RECT 0.048 80.640 16.672 80.736 ;
      RECT 0.048 81.408 16.672 81.504 ;
      RECT 0.048 82.176 16.672 82.272 ;
      RECT 0.048 82.944 16.672 83.040 ;
      RECT 0.048 83.712 16.672 83.808 ;
    END
  END VSS
  PIN VDD
    DIRECTION INOUT ;
    USE POWER ;
    PORT
      LAYER M4_m ;
      RECT 0.048 0.384 16.672 0.480 ;
      RECT 0.048 1.152 16.672 1.248 ;
      RECT 0.048 1.920 16.672 2.016 ;
      RECT 0.048 2.688 16.672 2.784 ;
      RECT 0.048 3.456 16.672 3.552 ;
      RECT 0.048 4.224 16.672 4.320 ;
      RECT 0.048 4.992 16.672 5.088 ;
      RECT 0.048 5.760 16.672 5.856 ;
      RECT 0.048 6.528 16.672 6.624 ;
      RECT 0.048 7.296 16.672 7.392 ;
      RECT 0.048 8.064 16.672 8.160 ;
      RECT 0.048 8.832 16.672 8.928 ;
      RECT 0.048 9.600 16.672 9.696 ;
      RECT 0.048 10.368 16.672 10.464 ;
      RECT 0.048 11.136 16.672 11.232 ;
      RECT 0.048 11.904 16.672 12.000 ;
      RECT 0.048 12.672 16.672 12.768 ;
      RECT 0.048 13.440 16.672 13.536 ;
      RECT 0.048 14.208 16.672 14.304 ;
      RECT 0.048 14.976 16.672 15.072 ;
      RECT 0.048 15.744 16.672 15.840 ;
      RECT 0.048 16.512 16.672 16.608 ;
      RECT 0.048 17.280 16.672 17.376 ;
      RECT 0.048 18.048 16.672 18.144 ;
      RECT 0.048 18.816 16.672 18.912 ;
      RECT 0.048 19.584 16.672 19.680 ;
      RECT 0.048 20.352 16.672 20.448 ;
      RECT 0.048 21.120 16.672 21.216 ;
      RECT 0.048 21.888 16.672 21.984 ;
      RECT 0.048 22.656 16.672 22.752 ;
      RECT 0.048 23.424 16.672 23.520 ;
      RECT 0.048 24.192 16.672 24.288 ;
      RECT 0.048 24.960 16.672 25.056 ;
      RECT 0.048 25.728 16.672 25.824 ;
      RECT 0.048 26.496 16.672 26.592 ;
      RECT 0.048 27.264 16.672 27.360 ;
      RECT 0.048 28.032 16.672 28.128 ;
      RECT 0.048 28.800 16.672 28.896 ;
      RECT 0.048 29.568 16.672 29.664 ;
      RECT 0.048 30.336 16.672 30.432 ;
      RECT 0.048 31.104 16.672 31.200 ;
      RECT 0.048 31.872 16.672 31.968 ;
      RECT 0.048 32.640 16.672 32.736 ;
      RECT 0.048 33.408 16.672 33.504 ;
      RECT 0.048 34.176 16.672 34.272 ;
      RECT 0.048 34.944 16.672 35.040 ;
      RECT 0.048 35.712 16.672 35.808 ;
      RECT 0.048 36.480 16.672 36.576 ;
      RECT 0.048 37.248 16.672 37.344 ;
      RECT 0.048 38.016 16.672 38.112 ;
      RECT 0.048 38.784 16.672 38.880 ;
      RECT 0.048 39.552 16.672 39.648 ;
      RECT 0.048 40.320 16.672 40.416 ;
      RECT 0.048 41.088 16.672 41.184 ;
      RECT 0.048 41.856 16.672 41.952 ;
      RECT 0.048 42.624 16.672 42.720 ;
      RECT 0.048 43.392 16.672 43.488 ;
      RECT 0.048 44.160 16.672 44.256 ;
      RECT 0.048 44.928 16.672 45.024 ;
      RECT 0.048 45.696 16.672 45.792 ;
      RECT 0.048 46.464 16.672 46.560 ;
      RECT 0.048 47.232 16.672 47.328 ;
      RECT 0.048 48.000 16.672 48.096 ;
      RECT 0.048 48.768 16.672 48.864 ;
      RECT 0.048 49.536 16.672 49.632 ;
      RECT 0.048 50.304 16.672 50.400 ;
      RECT 0.048 51.072 16.672 51.168 ;
      RECT 0.048 51.840 16.672 51.936 ;
      RECT 0.048 52.608 16.672 52.704 ;
      RECT 0.048 53.376 16.672 53.472 ;
      RECT 0.048 54.144 16.672 54.240 ;
      RECT 0.048 54.912 16.672 55.008 ;
      RECT 0.048 55.680 16.672 55.776 ;
      RECT 0.048 56.448 16.672 56.544 ;
      RECT 0.048 57.216 16.672 57.312 ;
      RECT 0.048 57.984 16.672 58.080 ;
      RECT 0.048 58.752 16.672 58.848 ;
      RECT 0.048 59.520 16.672 59.616 ;
      RECT 0.048 60.288 16.672 60.384 ;
      RECT 0.048 61.056 16.672 61.152 ;
      RECT 0.048 61.824 16.672 61.920 ;
      RECT 0.048 62.592 16.672 62.688 ;
      RECT 0.048 63.360 16.672 63.456 ;
      RECT 0.048 64.128 16.672 64.224 ;
      RECT 0.048 64.896 16.672 64.992 ;
      RECT 0.048 65.664 16.672 65.760 ;
      RECT 0.048 66.432 16.672 66.528 ;
      RECT 0.048 67.200 16.672 67.296 ;
      RECT 0.048 67.968 16.672 68.064 ;
      RECT 0.048 68.736 16.672 68.832 ;
      RECT 0.048 69.504 16.672 69.600 ;
      RECT 0.048 70.272 16.672 70.368 ;
      RECT 0.048 71.040 16.672 71.136 ;
      RECT 0.048 71.808 16.672 71.904 ;
      RECT 0.048 72.576 16.672 72.672 ;
      RECT 0.048 73.344 16.672 73.440 ;
      RECT 0.048 74.112 16.672 74.208 ;
      RECT 0.048 74.880 16.672 74.976 ;
      RECT 0.048 75.648 16.672 75.744 ;
      RECT 0.048 76.416 16.672 76.512 ;
      RECT 0.048 77.184 16.672 77.280 ;
      RECT 0.048 77.952 16.672 78.048 ;
      RECT 0.048 78.720 16.672 78.816 ;
      RECT 0.048 79.488 16.672 79.584 ;
      RECT 0.048 80.256 16.672 80.352 ;
      RECT 0.048 81.024 16.672 81.120 ;
      RECT 0.048 81.792 16.672 81.888 ;
      RECT 0.048 82.560 16.672 82.656 ;
      RECT 0.048 83.328 16.672 83.424 ;
    END
  END VDD
  OBS
    LAYER M1_m ;
    RECT 0 0 16.720 84.000 ;
    LAYER M2_m ;
    RECT 0 0 16.720 84.000 ;
    LAYER M3_m ;
    RECT 0.059 0.000 16.720 84.000 ;
    LAYER M4_m ;
    RECT 0.059 0.111 16.720 0.423 ;
    RECT 0.059 0.543 16.720 0.807 ;
    RECT 0.059 0.927 16.720 1.239 ;
    RECT 0.059 1.359 16.720 1.623 ;
    RECT 0.059 1.743 16.720 2.055 ;
    RECT 0.059 2.175 16.720 2.439 ;
    RECT 0.059 2.559 16.720 2.871 ;
    RECT 0.059 2.991 16.720 3.255 ;
    RECT 0.059 3.375 16.720 3.687 ;
    RECT 0.059 3.807 16.720 4.071 ;
    RECT 0.059 4.191 16.720 4.503 ;
    RECT 0.059 4.623 16.720 4.887 ;
    RECT 0.059 5.007 16.720 5.319 ;
    RECT 0.059 5.439 16.720 5.703 ;
    RECT 0.059 5.823 16.720 6.135 ;
    RECT 0.059 6.255 16.720 6.519 ;
    RECT 0.059 6.639 16.720 6.951 ;
    RECT 0.059 7.071 16.720 7.335 ;
    RECT 0.059 7.455 16.720 7.767 ;
    RECT 0.059 7.887 16.720 8.151 ;
    RECT 0.059 8.271 16.720 8.583 ;
    RECT 0.059 8.703 16.720 8.967 ;
    RECT 0.059 9.087 16.720 9.399 ;
    RECT 0.059 9.519 16.720 9.783 ;
    RECT 0.059 9.903 16.720 10.215 ;
    RECT 0.059 10.335 16.720 10.599 ;
    RECT 0.059 10.719 16.720 11.031 ;
    RECT 0.059 11.151 16.720 11.415 ;
    RECT 0.059 11.535 16.720 11.847 ;
    RECT 0.059 11.967 16.720 12.231 ;
    RECT 0.059 12.351 16.720 12.663 ;
    RECT 0.059 12.783 16.720 13.047 ;
    RECT 0.059 13.167 16.720 13.479 ;
    RECT 0.059 13.599 16.720 13.863 ;
    RECT 0.059 13.983 16.720 14.295 ;
    RECT 0.059 14.415 16.720 14.679 ;
    RECT 0.059 14.799 16.720 15.111 ;
    RECT 0.059 15.231 16.720 15.495 ;
    RECT 0.059 15.615 16.720 15.927 ;
    RECT 0.059 16.047 16.720 16.311 ;
    RECT 0.059 16.431 16.720 16.743 ;
    RECT 0.059 16.863 16.720 17.127 ;
    RECT 0.059 17.247 16.720 17.559 ;
    RECT 0.059 17.679 16.720 17.943 ;
    RECT 0.059 18.063 16.720 18.375 ;
    RECT 0.059 18.495 16.720 18.759 ;
    RECT 0.059 18.879 16.720 19.191 ;
    RECT 0.059 19.311 16.720 19.575 ;
    RECT 0.059 19.695 16.720 20.007 ;
    RECT 0.059 20.127 16.720 20.391 ;
    RECT 0.059 20.511 16.720 20.823 ;
    RECT 0.059 20.943 16.720 21.207 ;
    RECT 0.059 21.327 16.720 21.639 ;
    RECT 0.059 21.759 16.720 22.023 ;
    RECT 0.059 22.143 16.720 22.455 ;
    RECT 0.059 22.575 16.720 22.839 ;
    RECT 0.059 22.959 16.720 23.271 ;
    RECT 0.059 23.391 16.720 23.655 ;
    RECT 0.059 23.775 16.720 24.087 ;
    RECT 0.059 24.207 16.720 24.471 ;
    RECT 0.059 24.591 16.720 24.903 ;
    RECT 0.059 25.023 16.720 25.287 ;
    RECT 0.059 25.407 16.720 25.719 ;
    RECT 0.059 25.839 16.720 26.151 ;
    RECT 0.059 26.271 16.720 26.583 ;
    RECT 0.059 26.703 16.720 26.967 ;
    RECT 0.059 27.087 16.720 27.399 ;
    RECT 0.059 27.519 16.720 27.783 ;
    RECT 0.059 27.903 16.720 28.215 ;
    RECT 0.059 28.335 16.720 28.599 ;
    RECT 0.059 28.719 16.720 29.031 ;
    RECT 0.059 29.151 16.720 29.415 ;
    RECT 0.059 29.535 16.720 29.847 ;
    RECT 0.059 29.967 16.720 30.231 ;
    RECT 0.059 30.351 16.720 30.663 ;
    RECT 0.059 30.783 16.720 31.047 ;
    RECT 0.059 31.167 16.720 31.479 ;
    RECT 0.059 31.599 16.720 31.863 ;
    RECT 0.059 31.983 16.720 32.295 ;
    RECT 0.059 32.415 16.720 32.679 ;
    RECT 0.059 32.799 16.720 33.111 ;
    RECT 0.059 33.231 16.720 33.495 ;
    RECT 0.059 33.615 16.720 33.927 ;
    RECT 0.059 34.047 16.720 34.311 ;
    RECT 0.059 34.431 16.720 34.743 ;
    RECT 0.059 34.863 16.720 35.127 ;
    RECT 0.059 35.247 16.720 35.559 ;
    RECT 0.059 35.679 16.720 35.943 ;
    RECT 0.059 36.063 16.720 36.375 ;
    RECT 0.059 36.495 16.720 36.759 ;
    RECT 0.059 36.879 16.720 37.191 ;
    RECT 0.059 37.311 16.720 37.575 ;
    RECT 0.059 37.695 16.720 38.007 ;
    RECT 0.059 38.127 16.720 38.391 ;
    RECT 0.059 38.511 16.720 38.823 ;
    RECT 0.059 38.943 16.720 39.207 ;
    RECT 0.059 39.327 16.720 39.639 ;
    RECT 0.059 39.759 16.720 40.023 ;
    RECT 0.059 40.143 16.720 40.455 ;
    RECT 0.059 40.575 16.720 40.839 ;
    RECT 0.059 40.959 16.720 41.271 ;
    RECT 0.059 41.391 16.720 41.655 ;
    RECT 0.059 41.775 16.720 42.087 ;
    RECT 0.059 42.207 16.720 42.471 ;
    RECT 0.059 42.591 16.720 42.903 ;
    RECT 0.059 43.023 16.720 43.287 ;
    RECT 0.059 43.407 16.720 43.719 ;
    RECT 0.059 43.839 16.720 44.103 ;
    RECT 0.059 44.223 16.720 44.535 ;
    RECT 0.059 44.655 16.720 44.919 ;
    RECT 0.059 45.039 16.720 45.351 ;
    RECT 0.059 45.471 16.720 45.735 ;
    RECT 0.059 45.855 16.720 46.167 ;
    RECT 0.059 46.287 16.720 46.551 ;
    RECT 0.059 46.671 16.720 46.983 ;
    RECT 0.059 47.103 16.720 47.367 ;
    RECT 0.059 47.487 16.720 47.799 ;
    RECT 0.059 47.919 16.720 48.183 ;
    RECT 0.059 48.303 16.720 48.615 ;
    RECT 0.059 48.735 16.720 48.999 ;
    RECT 0.059 49.119 16.720 49.431 ;
    RECT 0.059 49.551 16.720 49.815 ;
    RECT 0.059 49.935 16.720 50.247 ;
    RECT 0.059 50.367 16.720 50.631 ;
    RECT 0.059 50.751 16.720 51.063 ;
    RECT 0.059 51.183 16.720 51.447 ;
    RECT 0.059 51.567 16.720 51.879 ;
    RECT 0.059 51.999 16.720 52.311 ;
    RECT 0.059 52.431 16.720 52.743 ;
    RECT 0.059 52.863 16.720 53.127 ;
    RECT 0.059 53.247 16.720 53.559 ;
    RECT 0.059 53.679 16.720 53.943 ;
    RECT 0.059 54.063 16.720 54.375 ;
    RECT 0.059 54.495 16.720 54.759 ;
    RECT 0.059 54.879 16.720 55.191 ;
    RECT 0.059 55.311 16.720 55.575 ;
    RECT 0.059 55.695 16.720 56.007 ;
    RECT 0.059 56.127 16.720 56.391 ;
    RECT 0.059 56.511 16.720 56.823 ;
    RECT 0.059 56.943 16.720 57.207 ;
    RECT 0.059 57.327 16.720 57.639 ;
    RECT 0.059 57.759 16.720 58.023 ;
    RECT 0.059 58.143 16.720 58.455 ;
    RECT 0.059 58.575 16.720 58.839 ;
    RECT 0.059 58.959 16.720 59.271 ;
    RECT 0.059 59.391 16.720 59.655 ;
    RECT 0.059 59.775 16.720 60.087 ;
    RECT 0.059 60.207 16.720 60.471 ;
    RECT 0.059 60.591 16.720 60.903 ;
    RECT 0.059 61.023 16.720 61.287 ;
    RECT 0.059 61.407 16.720 61.719 ;
    RECT 0.059 61.839 16.720 62.103 ;
    RECT 0.059 62.223 16.720 62.535 ;
    RECT 0.059 62.655 16.720 62.919 ;
    RECT 0.059 63.039 16.720 63.351 ;
    RECT 0.059 63.471 16.720 63.735 ;
    RECT 0.059 63.855 16.720 64.167 ;
    RECT 0.059 64.287 16.720 64.551 ;
    RECT 0.059 64.671 16.720 64.983 ;
    RECT 0.059 65.103 16.720 65.367 ;
    RECT 0.059 65.487 16.720 65.799 ;
    RECT 0.059 65.919 16.720 66.183 ;
    RECT 0.059 66.303 16.720 66.615 ;
    RECT 0.059 66.735 16.720 66.999 ;
    RECT 0.059 67.119 16.720 67.431 ;
    RECT 0.059 67.551 16.720 67.815 ;
    RECT 0.059 67.935 16.720 68.247 ;
    RECT 0.059 68.367 16.720 68.631 ;
    RECT 0.059 68.751 16.720 69.063 ;
    RECT 0.059 69.183 16.720 69.447 ;
    RECT 0.059 69.567 16.720 69.879 ;
    RECT 0.059 69.999 16.720 70.263 ;
    RECT 0.059 70.383 16.720 70.695 ;
    RECT 0.059 70.815 16.720 71.079 ;
    RECT 0.059 71.199 16.720 71.511 ;
    RECT 0.059 71.631 16.720 71.895 ;
    RECT 0.059 72.015 16.720 72.327 ;
    RECT 0.059 72.447 16.720 72.711 ;
    RECT 0.059 72.831 16.720 73.143 ;
    RECT 0.059 73.263 16.720 73.527 ;
    RECT 0.059 73.647 16.720 73.959 ;
    RECT 0.059 74.079 16.720 74.343 ;
    RECT 0.059 74.463 16.720 74.775 ;
    RECT 0.059 74.895 16.720 75.159 ;
    RECT 0.059 75.279 16.720 75.591 ;
    RECT 0.059 75.711 16.720 75.975 ;
    RECT 0.059 76.095 16.720 76.407 ;
    RECT 0.059 76.527 16.720 76.791 ;
    RECT 0.059 76.911 16.720 77.223 ;
    RECT 0.059 77.343 16.720 77.607 ;
    RECT 0.059 77.727 16.720 78.039 ;
    RECT 0.059 78.159 16.720 78.471 ;
    RECT 0.059 78.591 16.720 78.903 ;
    RECT 0.059 79.023 16.720 79.287 ;
    RECT 0.059 79.407 16.720 79.719 ;
    RECT 0.059 79.839 16.720 80.103 ;
    RECT 0.059 80.223 16.720 80.535 ;
    RECT 0.059 80.655 16.720 80.919 ;
    RECT 0.059 81.039 16.720 81.351 ;
    RECT 0.059 81.471 16.720 81.735 ;
    RECT 0.059 81.855 16.720 82.215 ;
    RECT 0.059 82.335 16.720 82.599 ;
    RECT 0.059 82.719 16.720 83.031 ;
    RECT 0.059 83.151 16.720 84.000 ;
  END
END fakeram7_512x64_upper

END LIBRARY
